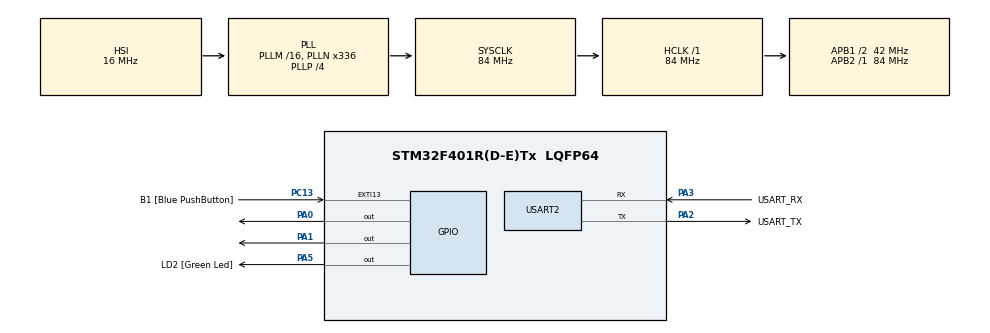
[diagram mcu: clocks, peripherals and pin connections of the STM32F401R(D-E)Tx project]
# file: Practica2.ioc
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Mcu.Family=STM32F4
Mcu.Name=STM32F401R(D-E)Tx
Mcu.Package=LQFP64
NVIC.PriorityGroup=NVIC_PRIORITYGROUP_0
PA0-WKUP.Signal=GPIO_Output
PA1.Signal=GPIO_Output
PA13.GPIO_Label=TMS
PA13.Mode=Serial_Wire
PA13.Signal=SYS_JTMS-SWDIO
PA14.GPIO_Label=TCK
PA14.Mode=Serial_Wire
PA14.Signal=SYS_JTCK-SWCLK
PA2.GPIO_Label=USART_TX
PA2.GPIO_Mode=GPIO_MODE_AF_PP
PA2.GPIO_PuPd=GPIO_NOPULL
PA2.GPIO_Speed=GPIO_SPEED_FREQ_LOW
PA2.Mode=Asynchronous
PA2.Signal=USART2_TX
PA3.GPIO_Label=USART_RX
PA3.GPIO_Mode=GPIO_MODE_AF_PP
PA3.GPIO_PuPd=GPIO_NOPULL
PA3.GPIO_Speed=GPIO_SPEED_FREQ_LOW
PA3.Mode=Asynchronous
PA3.Signal=USART2_RX
PA5.GPIO_Label=LD2 [Green Led]
PA5.GPIO_Mode=GPIO_MODE_OUTPUT_PP
PA5.GPIO_PuPd=GPIO_NOPULL
PA5.GPIO_Speed=GPIO_SPEED_FREQ_LOW
PA5.Signal=GPIO_Output
PB3.GPIO_Label=SWO
PB3.Signal=SYS_JTDO-SWO
PC13-ANTI_TAMP.GPIO_Label=B1 [Blue PushButton]
PC13-ANTI_TAMP.GPIO_ModeDefaultEXTI=GPIO_MODE_IT_FALLING
PC13-ANTI_TAMP.GPIO_PuPd=GPIO_NOPULL
PC13-ANTI_TAMP.Signal=GPXTI13
PC14-OSC32_IN.Mode=LSE-External-Oscillator
PC14-OSC32_IN.Signal=RCC_OSC32_IN
PC15-OSC32_OUT.Mode=LSE-External-Oscillator
PC15-OSC32_OUT.Signal=RCC_OSC32_OUT
PH0\ -\ OSC_IN.Mode=HSE-External-Oscillator
PH0\ -\ OSC_IN.Signal=RCC_OSC_IN
PH1\ -\ OSC_OUT.Mode=HSE-External-Oscillator
PH1\ -\ OSC_OUT.Signal=RCC_OSC_OUT
ProjectManager.HeapSize=0x200
ProjectManager.StackSize=0x400
ProjectManager.TargetToolchain=STM32CubeIDE
RCC.48MHZClocksFreq_Value=48000000
RCC.AHBFreq_Value=84000000
RCC.APB1CLKDivider=RCC_HCLK_DIV2
RCC.APB1Freq_Value=42000000
RCC.APB1TimFreq_Value=84000000
RCC.APB2Freq_Value=84000000
RCC.APB2TimFreq_Value=84000000
RCC.CortexFreq_Value=84000000
RCC.HCLKFreq_Value=84000000
RCC.HSE_VALUE=8000000
RCC.HSI_VALUE=16000000
RCC.PLLN=336
RCC.PLLP=RCC_PLLP_DIV4
RCC.PLLQ=7
RCC.SYSCLKFreq_VALUE=84000000
RCC.SYSCLKSource=RCC_SYSCLKSOURCE_PLLCLK
RCC.VCOOutputFreq_Value=336000000
USART2.VirtualMode=VM_ASYNC
board=NUCLEO-F401RE

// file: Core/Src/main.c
#include "main.h"
#include "API_debounce.h"
#include "API_delay.h"

//Led2 (color verde) es el unico que trae la placa ubicado en el pin5 GPIOA

/* USER CODE BEGIN Includes */
static delay_t ledDelay;                   // Retardo no bloqueante para los LEDs
static debounceState_t state;              // Estado actual de la MEF Anti-Rebote
UART_HandleTypeDef huart2;          // Handler de UART para comunicación serial (si es necesario)

void SystemClock_Config(void);
static void MX_GPIO_Init(void);
static void MX_USART2_UART_Init(void);
void Error_Handler(void);
/**
 * @brief  Punto de entrada de la aplicación.
 * @retval int
 */

int main(void) {
	/* Configuración del MCU */
	HAL_Init();
	SystemClock_Config();
	MX_GPIO_Init();
	MX_USART2_UART_Init();

	// Inicializando la estructura para el retardo no bloqueante
	delayInit(&ledDelay, 40);

	// Inicializando la MEF Anti-Rebote con el estado inicial BUTTON_UP
	debounceFSM_init(&state, BUTTON_UP);

	uint32_t toggleFrequency = 100;

	/* Bucle infinito */
	while (1) {
		debounceFSM_update(&state, &ledDelay);

		if (readKey())
		{
			// Cambia la frecuencia de alternancia entre 100 ms y 500 ms
			if (toggleFrequency == 100)
			{
				toggleFrequency = 500;
			}
			else
			{
				toggleFrequency = 100;
			}

			delayWrite(&ledDelay, toggleFrequency);
		}

		// Alternar LED2 cada duración del retraso
		if (delayRead(&ledDelay))
		{
			HAL_GPIO_TogglePin(LD2_GPIO_Port, LD2_Pin);
		}
	}

	return 0;
}

/* Configuración del sistema de reloj */
void SystemClock_Config(void) {
	RCC_OscInitTypeDef RCC_OscInitStruct = { 0 };
	RCC_ClkInitTypeDef RCC_ClkInitStruct = { 0 };

	/** Configurar la tensión de salida del regulador interno principal
	 */
	__HAL_RCC_PWR_CLK_ENABLE();
	__HAL_PWR_VOLTAGESCALING_CONFIG(PWR_REGULATOR_VOLTAGE_SCALE2);

	/** Inicializar los osciladores RCC según los parámetros especificados
	 * en la estructura RCC_OscInitStruct.
	 */
	RCC_OscInitStruct.OscillatorType = RCC_OSCILLATORTYPE_HSI;
	RCC_OscInitStruct.HSIState = RCC_HSI_ON;
	RCC_OscInitStruct.HSICalibrationValue = RCC_HSICALIBRATION_DEFAULT;
	RCC_OscInitStruct.PLL.PLLState = RCC_PLL_ON;
	RCC_OscInitStruct.PLL.PLLSource = RCC_PLLSOURCE_HSI;
	RCC_OscInitStruct.PLL.PLLM = 16;
	RCC_OscInitStruct.PLL.PLLN = 336;
	RCC_OscInitStruct.PLL.PLLP = RCC_PLLP_DIV4;
	RCC_OscInitStruct.PLL.PLLQ = 7;
	if (HAL_RCC_OscConfig(&RCC_OscInitStruct) != HAL_OK) {
		Error_Handler();
	}

	/** Inicializar los relojes de la CPU, AHB y APB
	 */
	RCC_ClkInitStruct.ClockType = RCC_CLOCKTYPE_HCLK | RCC_CLOCKTYPE_SYSCLK
			| RCC_CLOCKTYPE_PCLK1 | RCC_CLOCKTYPE_PCLK2;
	RCC_ClkInitStruct.SYSCLKSource = RCC_SYSCLKSOURCE_PLLCLK;
	RCC_ClkInitStruct.AHBCLKDivider = RCC_SYSCLK_DIV1;
	RCC_ClkInitStruct.APB1CLKDivider = RCC_HCLK_DIV2;
	RCC_ClkInitStruct.APB2CLKDivider = RCC_HCLK_DIV1;

	if (HAL_RCC_ClockConfig(&RCC_ClkInitStruct, FLASH_LATENCY_2) != HAL_OK) {
		Error_Handler();
	}
}

static void MX_USART2_UART_Init(void) {

	huart2.Instance = USART2;
	huart2.Init.BaudRate = 115200;
	huart2.Init.WordLength = UART_WORDLENGTH_8B;
	huart2.Init.StopBits = UART_STOPBITS_1;
	huart2.Init.Parity = UART_PARITY_NONE;
	huart2.Init.Mode = UART_MODE_TX_RX;
	huart2.Init.HwFlowCtl = UART_HWCONTROL_NONE;
	huart2.Init.OverSampling = UART_OVERSAMPLING_16;
	if (HAL_UART_Init(&huart2) != HAL_OK) {
		Error_Handler();
	}
}

static void MX_GPIO_Init(void) {
	GPIO_InitTypeDef GPIO_InitStruct = { 0 };

	/* GPIO Ports Clock Enable */
	__HAL_RCC_GPIOC_CLK_ENABLE();
	__HAL_RCC_GPIOH_CLK_ENABLE();
	__HAL_RCC_GPIOA_CLK_ENABLE();
	__HAL_RCC_GPIOB_CLK_ENABLE();

	/*Configure GPIO pin Output Level */
	HAL_GPIO_WritePin(GPIOA, LD1_Pin | LD3_Pin | LD2_Pin, GPIO_PIN_RESET);

	/*Cofigure GPIO pin : B1_Pin */
	GPIO_InitStruct.Pin = B1_Pin;
	GPIO_InitStruct.Mode = GPIO_MODE_IT_FALLING;
	GPIO_InitStruct.Pull = GPIO_NOPULL;
	HAL_GPIO_Init(B1_GPIO_Port, &GPIO_InitStruct);

	/*Configure GPIO pin : L1,L2,L3_Pin */
	GPIO_InitStruct.Pin = LD1_Pin | LD3_Pin | LD2_Pin;
	GPIO_InitStruct.Mode = GPIO_MODE_OUTPUT_PP;
	GPIO_InitStruct.Pull = GPIO_NOPULL;
	GPIO_InitStruct.Speed = GPIO_SPEED_FREQ_LOW;
	HAL_GPIO_Init(GPIOA, &GPIO_InitStruct);

}

void Error_Handler(void) {

	__disable_irq();
	while (1) {
	}
	/* USER CODE END Error_Handler_Debug */
}
